VERSION 5.7 ;
  NOWIREEXTENSIONATPIN ON ;
  DIVIDERCHAR "/" ;
  BUSBITCHARS "[]" ;
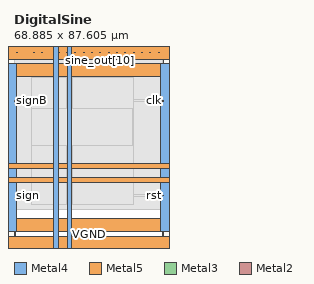
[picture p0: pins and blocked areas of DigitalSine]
MACRO DigitalSine
  CLASS BLOCK ;
  FOREIGN DigitalSine ;
  ORIGIN 0.000 0.000 ;
  SIZE 68.885 BY 87.605 ;
  PIN VGND
    DIRECTION INOUT ;
    USE GROUND ;
    PORT
      LAYER Metal4 ;
        RECT -12.740 -3.380 -6.740 90.320 ;
    END
    PORT
      LAYER Metal5 ;
        RECT -12.740 -3.380 81.380 2.620 ;
    END
    PORT
      LAYER Metal5 ;
        RECT -12.740 84.320 81.380 90.320 ;
    END
    PORT
      LAYER Metal4 ;
        RECT 75.380 -3.380 81.380 90.320 ;
    END
    PORT
      LAYER Metal4 ;
        RECT 24.460 -3.380 26.660 90.320 ;
    END
    PORT
      LAYER Metal5 ;
        RECT -12.740 33.820 81.380 36.020 ;
    END
  END VGND
  PIN VPWR
    DIRECTION INOUT ;
    USE POWER ;
    PORT
      LAYER Metal4 ;
        RECT -4.740 4.620 1.260 82.320 ;
    END
    PORT
      LAYER Metal5 ;
        RECT -4.740 4.620 73.380 10.620 ;
    END
    PORT
      LAYER Metal5 ;
        RECT -4.740 76.320 73.380 82.320 ;
    END
    PORT
      LAYER Metal4 ;
        RECT 67.380 4.620 73.380 82.320 ;
    END
    PORT
      LAYER Metal4 ;
        RECT 18.260 -3.380 20.460 90.320 ;
    END
    PORT
      LAYER Metal5 ;
        RECT -12.740 27.620 81.380 29.820 ;
    END
  END VPWR
  PIN clk
    DIRECTION INPUT ;
    USE SIGNAL ;
    ANTENNAGATEAREA 0.725400 ;
    PORT
      LAYER Metal3 ;
        RECT 68.485 64.900 68.885 65.300 ;
    END
  END clk
  PIN rst
    DIRECTION INPUT ;
    USE SIGNAL ;
    ANTENNAGATEAREA 0.180700 ;
    PORT
      LAYER Metal3 ;
        RECT 68.485 21.220 68.885 21.620 ;
    END
  END rst
  PIN sign
    DIRECTION OUTPUT ;
    USE SIGNAL ;
    ANTENNADIFFAREA 0.706800 ;
    PORT
      LAYER Metal3 ;
        RECT 0.000 21.220 0.400 21.620 ;
    END
  END sign
  PIN signB
    DIRECTION OUTPUT ;
    USE SIGNAL ;
    ANTENNADIFFAREA 0.706800 ;
    PORT
      LAYER Metal3 ;
        RECT 0.000 64.900 0.400 65.300 ;
    END
  END signB
  PIN sine_out[0]
    DIRECTION OUTPUT ;
    USE SIGNAL ;
    ANTENNADIFFAREA 0.706800 ;
    PORT
      LAYER Metal2 ;
        RECT 1.240 87.205 1.640 87.605 ;
    END
  END sine_out[0]
  PIN sine_out[10]
    DIRECTION OUTPUT ;
    USE SIGNAL ;
    ANTENNADIFFAREA 0.706800 ;
    PORT
      LAYER Metal2 ;
        RECT 39.640 87.205 40.040 87.605 ;
    END
  END sine_out[10]
  PIN sine_out[11]
    DIRECTION OUTPUT ;
    USE SIGNAL ;
    ANTENNADIFFAREA 0.706800 ;
    PORT
      LAYER Metal2 ;
        RECT 43.480 87.205 43.880 87.605 ;
    END
  END sine_out[11]
  PIN sine_out[12]
    DIRECTION OUTPUT ;
    USE SIGNAL ;
    ANTENNADIFFAREA 0.706800 ;
    PORT
      LAYER Metal2 ;
        RECT 47.320 87.205 47.720 87.605 ;
    END
  END sine_out[12]
  PIN sine_out[13]
    DIRECTION OUTPUT ;
    USE SIGNAL ;
    ANTENNADIFFAREA 0.706800 ;
    PORT
      LAYER Metal2 ;
        RECT 51.160 87.205 51.560 87.605 ;
    END
  END sine_out[13]
  PIN sine_out[14]
    DIRECTION OUTPUT ;
    USE SIGNAL ;
    ANTENNADIFFAREA 0.706800 ;
    PORT
      LAYER Metal2 ;
        RECT 55.000 87.205 55.400 87.605 ;
    END
  END sine_out[14]
  PIN sine_out[15]
    DIRECTION OUTPUT ;
    USE SIGNAL ;
    ANTENNADIFFAREA 0.706800 ;
    PORT
      LAYER Metal2 ;
        RECT 58.840 87.205 59.240 87.605 ;
    END
  END sine_out[15]
  PIN sine_out[16]
    DIRECTION OUTPUT ;
    USE SIGNAL ;
    ANTENNADIFFAREA 0.706800 ;
    PORT
      LAYER Metal2 ;
        RECT 62.680 87.205 63.080 87.605 ;
    END
  END sine_out[16]
  PIN sine_out[17]
    DIRECTION OUTPUT ;
    USE SIGNAL ;
    ANTENNADIFFAREA 0.706800 ;
    PORT
      LAYER Metal2 ;
        RECT 66.520 87.205 66.920 87.605 ;
    END
  END sine_out[17]
  PIN sine_out[1]
    DIRECTION OUTPUT ;
    USE SIGNAL ;
    ANTENNADIFFAREA 0.706800 ;
    PORT
      LAYER Metal2 ;
        RECT 5.080 87.205 5.480 87.605 ;
    END
  END sine_out[1]
  PIN sine_out[2]
    DIRECTION OUTPUT ;
    USE SIGNAL ;
    ANTENNADIFFAREA 0.706800 ;
    PORT
      LAYER Metal2 ;
        RECT 8.920 87.205 9.320 87.605 ;
    END
  END sine_out[2]
  PIN sine_out[3]
    DIRECTION OUTPUT ;
    USE SIGNAL ;
    ANTENNADIFFAREA 0.706800 ;
    PORT
      LAYER Metal2 ;
        RECT 12.760 87.205 13.160 87.605 ;
    END
  END sine_out[3]
  PIN sine_out[4]
    DIRECTION OUTPUT ;
    USE SIGNAL ;
    ANTENNADIFFAREA 0.706800 ;
    PORT
      LAYER Metal2 ;
        RECT 16.600 87.205 17.000 87.605 ;
    END
  END sine_out[4]
  PIN sine_out[5]
    DIRECTION OUTPUT ;
    USE SIGNAL ;
    ANTENNADIFFAREA 0.706800 ;
    PORT
      LAYER Metal2 ;
        RECT 20.440 87.205 20.840 87.605 ;
    END
  END sine_out[5]
  PIN sine_out[6]
    DIRECTION OUTPUT ;
    USE SIGNAL ;
    ANTENNADIFFAREA 0.706800 ;
    PORT
      LAYER Metal2 ;
        RECT 24.280 87.205 24.680 87.605 ;
    END
  END sine_out[6]
  PIN sine_out[7]
    DIRECTION OUTPUT ;
    USE SIGNAL ;
    ANTENNADIFFAREA 0.706800 ;
    PORT
      LAYER Metal2 ;
        RECT 28.120 87.205 28.520 87.605 ;
    END
  END sine_out[7]
  PIN sine_out[8]
    DIRECTION OUTPUT ;
    USE SIGNAL ;
    ANTENNADIFFAREA 0.706800 ;
    PORT
      LAYER Metal2 ;
        RECT 31.960 87.205 32.360 87.605 ;
    END
  END sine_out[8]
  PIN sine_out[9]
    DIRECTION OUTPUT ;
    USE SIGNAL ;
    ANTENNADIFFAREA 0.706800 ;
    PORT
      LAYER Metal2 ;
        RECT 35.800 87.205 36.200 87.605 ;
    END
  END sine_out[9]
  OBS
      LAYER GatPoly ;
        RECT 5.760 14.970 62.880 71.970 ;
      LAYER Metal1 ;
        RECT 5.760 14.900 62.880 72.040 ;
      LAYER Metal2 ;
        RECT 1.850 86.995 4.870 87.460 ;
        RECT 5.690 86.995 8.710 87.460 ;
        RECT 9.530 86.995 12.550 87.460 ;
        RECT 13.370 86.995 16.390 87.460 ;
        RECT 17.210 86.995 20.230 87.460 ;
        RECT 21.050 86.995 24.070 87.460 ;
        RECT 24.890 86.995 27.910 87.460 ;
        RECT 28.730 86.995 31.750 87.460 ;
        RECT 32.570 86.995 35.590 87.460 ;
        RECT 36.410 86.995 39.430 87.460 ;
        RECT 40.250 86.995 43.270 87.460 ;
        RECT 44.090 86.995 47.110 87.460 ;
        RECT 47.930 86.995 50.950 87.460 ;
        RECT 51.770 86.995 54.790 87.460 ;
        RECT 55.610 86.995 58.630 87.460 ;
        RECT 59.450 86.995 62.470 87.460 ;
        RECT 63.290 86.995 66.310 87.460 ;
        RECT 1.335 14.975 66.825 86.995 ;
      LAYER Metal3 ;
        RECT 0.400 65.510 68.485 86.620 ;
        RECT 0.610 64.690 68.275 65.510 ;
        RECT 0.400 21.830 68.485 64.690 ;
        RECT 0.610 21.010 68.275 21.830 ;
        RECT 0.400 15.020 68.485 21.010 ;
      LAYER Metal4 ;
        RECT 8.055 17.075 18.050 75.745 ;
        RECT 20.670 17.075 24.250 75.745 ;
        RECT 26.870 17.075 55.300 75.745 ;
      LAYER Metal5 ;
        RECT 8.015 44.420 54.865 61.420 ;
  END
END DigitalSine
END LIBRARY

